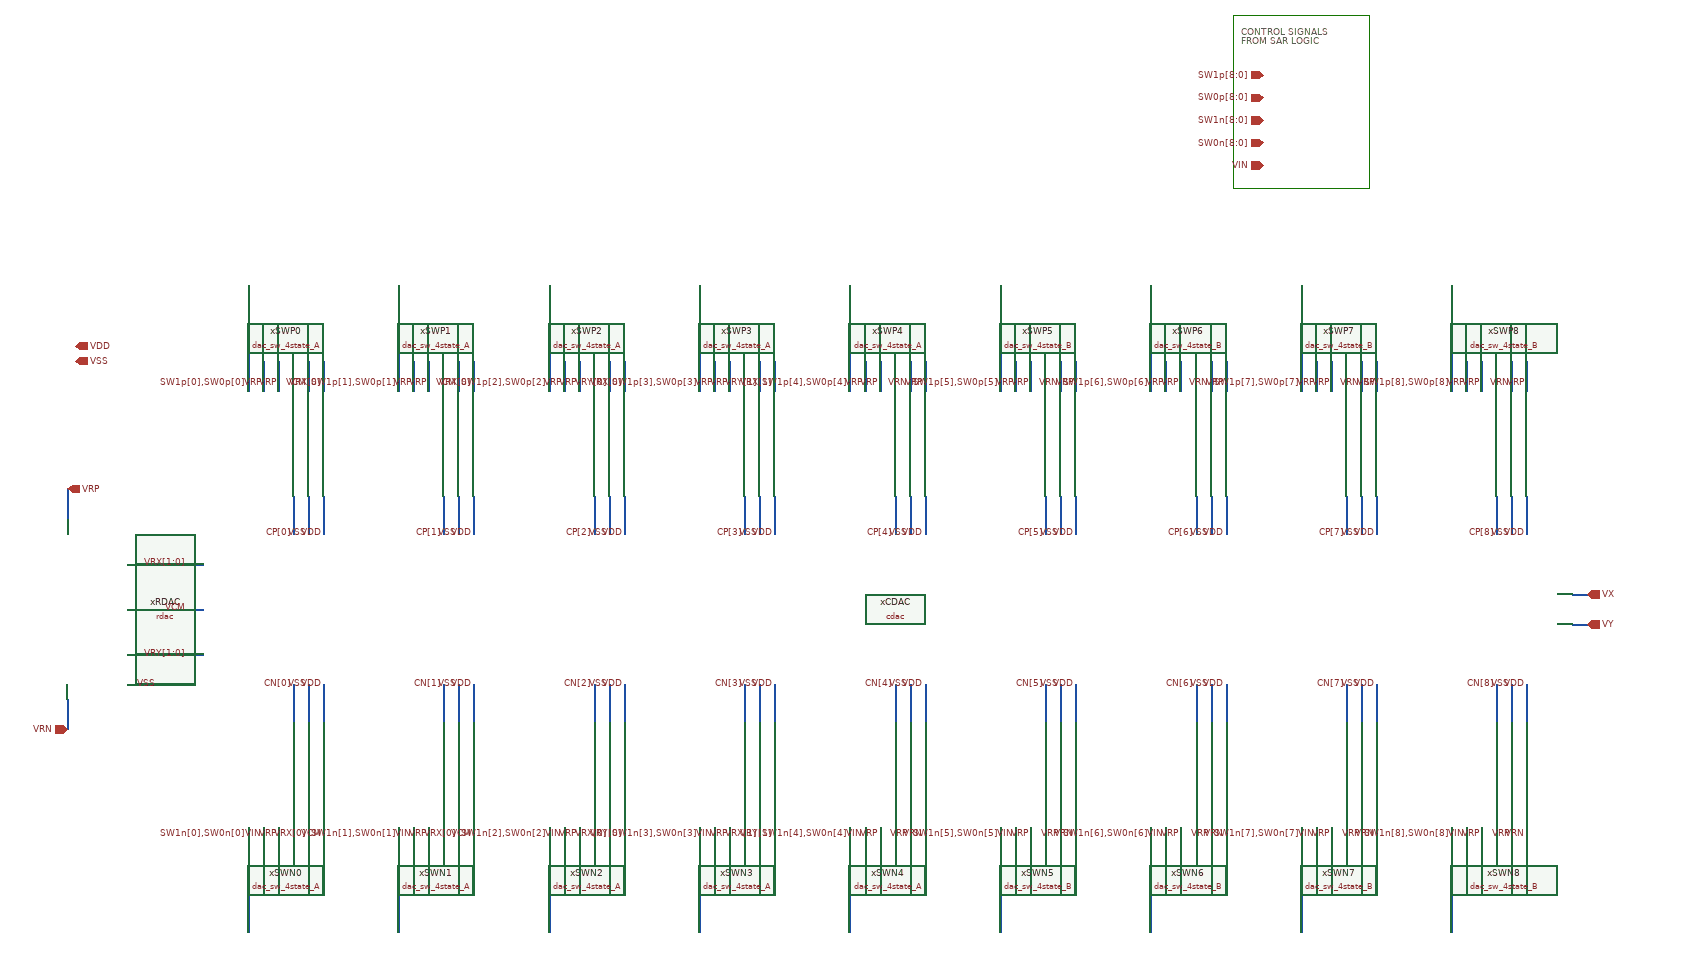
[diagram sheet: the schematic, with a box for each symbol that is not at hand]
v {xschem version=3.4.8RC file_version=1.3}
G {}
K {}
V {}
S {}
F {}
E {}
P 4 5 2070 -2150 2250 -2150 2250 -1920 2070 -1920 2070 -2150 {}
T {CONTROL SIGNALS
FROM SAR LOGIC} 2080 -2140 0 0 0.3 0.3 {}
N 520 -1520 520 -1480 {lab=VRP}
N 520 -1240 520 -1200 {lab=VRN}
N 600 -1260 640 -1260 {lab=VSS}
N 600 -1420 700 -1420 {lab=VRX[1:0]}
N 600 -1300 700 -1300 {lab=VRY[1:0]}
N 1660 -1690 1660 -1650 {lab=VRP}
N 1640 -1690 1640 -1650 {lab=VRN}
N 1600 -1690 1600 -1650 {lab=VRP}
N 1580 -1690 1580 -1650 {lab=VRP}
N 1660 -1510 1660 -1460 {lab=VDD}
N 1640 -1510 1640 -1460 {lab=VSS}
N 1620 -1510 1620 -1460 {lab=CP[4]}
N 1860 -1690 1860 -1650 {lab=VRP}
N 1840 -1690 1840 -1650 {lab=VRN}
N 1800 -1690 1800 -1650 {lab=VRP}
N 1780 -1690 1780 -1650 {lab=VRP}
N 1860 -1510 1860 -1460 {lab=VDD}
N 1840 -1510 1840 -1460 {lab=VSS}
N 1820 -1510 1820 -1460 {lab=CP[5]}
N 2060 -1690 2060 -1650 {lab=VRP}
N 2040 -1690 2040 -1650 {lab=VRN}
N 2000 -1690 2000 -1650 {lab=VRP}
N 1980 -1690 1980 -1650 {lab=VRP}
N 2060 -1510 2060 -1460 {lab=VDD}
N 2040 -1510 2040 -1460 {lab=VSS}
N 2020 -1510 2020 -1460 {lab=CP[6]}
N 2260 -1690 2260 -1650 {lab=VRP}
N 2240 -1690 2240 -1650 {lab=VRN}
N 2200 -1690 2200 -1650 {lab=VRP}
N 2180 -1690 2180 -1650 {lab=VRP}
N 2260 -1510 2260 -1460 {lab=VDD}
N 2240 -1510 2240 -1460 {lab=VSS}
N 2220 -1510 2220 -1460 {lab=CP[7]}
N 2440 -1690 2440 -1650 {lab=VRN}
N 2460 -1690 2460 -1650 {lab=VRP}
N 2400 -1690 2400 -1650 {lab=VRP}
N 2380 -1690 2380 -1650 {lab=VRP}
N 2460 -1510 2460 -1460 {lab=VDD}
N 2440 -1510 2440 -1460 {lab=VSS}
N 2420 -1510 2420 -1460 {lab=CP[8]}
N 1660 -1070 1660 -1030 {lab=VRN}
N 1640 -1070 1640 -1030 {lab=VRP}
N 1600 -1070 1600 -1030 {lab=VRP}
N 1580 -1070 1580 -1030 {lab=VIN}
N 1660 -1260 1660 -1210 {lab=VDD}
N 1640 -1260 1640 -1210 {lab=VSS}
N 1620 -1260 1620 -1210 {lab=CN[4]}
N 1860 -1070 1860 -1030 {lab=VRN}
N 1840 -1070 1840 -1030 {lab=VRP}
N 1800 -1070 1800 -1030 {lab=VRP}
N 1780 -1070 1780 -1030 {lab=VIN}
N 1860 -1260 1860 -1210 {lab=VDD}
N 1840 -1260 1840 -1210 {lab=VSS}
N 1820 -1260 1820 -1210 {lab=CN[5]}
N 2060 -1070 2060 -1030 {lab=VRN}
N 2040 -1070 2040 -1030 {lab=VRP}
N 2000 -1070 2000 -1030 {lab=VRP}
N 1980 -1070 1980 -1030 {lab=VIN}
N 2060 -1260 2060 -1210 {lab=VDD}
N 2040 -1260 2040 -1210 {lab=VSS}
N 2020 -1260 2020 -1210 {lab=CN[6]}
N 2260 -1070 2260 -1030 {lab=VRN}
N 2240 -1070 2240 -1030 {lab=VRP}
N 2200 -1070 2200 -1030 {lab=VRP}
N 2180 -1070 2180 -1030 {lab=VIN}
N 2260 -1260 2260 -1210 {lab=VDD}
N 2240 -1260 2240 -1210 {lab=VSS}
N 2220 -1260 2220 -1210 {lab=CN[7]}
N 2440 -1070 2440 -1030 {lab=VRP}
N 2460 -1070 2460 -1030 {lab=VRN}
N 2400 -1070 2400 -1030 {lab=VRP}
N 2380 -1070 2380 -1030 {lab=VIN}
N 2460 -1260 2460 -1210 {lab=VDD}
N 2440 -1260 2440 -1210 {lab=VSS}
N 2420 -1260 2420 -1210 {lab=CN[8]}
N 1560 -1790 1560 -1650 {lab=SW1p[4],SW0p[4]}
N 1560 -1070 1560 -930 {lab=SW1n[4],SW0n[4]}
N 1760 -1790 1760 -1650 {lab=SW1p[5],SW0p[5]}
N 1760 -1070 1760 -930 {lab=SW1n[5],SW0n[5]}
N 1960 -1790 1960 -1650 {lab=SW1p[6],SW0p[6]}
N 1960 -1070 1960 -930 {lab=SW1n[6],SW0n[6]}
N 2160 -1790 2160 -1650 {lab=SW1p[7],SW0p[7]}
N 2160 -1070 2160 -930 {lab=SW1n[7],SW0n[7]}
N 2360 -1790 2360 -1650 {lab=SW1p[8],SW0p[8]}
N 2360 -1070 2360 -930 {lab=SW1n[8],SW0n[8]}
N 800 -1690 800 -1650 {lab=VRP}
N 780 -1690 780 -1650 {lab=VRP}
N 860 -1510 860 -1460 {lab=VDD}
N 840 -1510 840 -1460 {lab=VSS}
N 820 -1510 820 -1460 {lab=CP[0]}
N 1000 -1690 1000 -1650 {lab=VRP}
N 980 -1690 980 -1650 {lab=VRP}
N 1060 -1510 1060 -1460 {lab=VDD}
N 1040 -1510 1040 -1460 {lab=VSS}
N 1020 -1510 1020 -1460 {lab=CP[1]}
N 1200 -1690 1200 -1650 {lab=VRP}
N 1180 -1690 1180 -1650 {lab=VRP}
N 1260 -1510 1260 -1460 {lab=VDD}
N 1240 -1510 1240 -1460 {lab=VSS}
N 1220 -1510 1220 -1460 {lab=CP[2]}
N 1400 -1690 1400 -1650 {lab=VRP}
N 1380 -1690 1380 -1650 {lab=VRP}
N 1460 -1510 1460 -1460 {lab=VDD}
N 1440 -1510 1440 -1460 {lab=VSS}
N 1420 -1510 1420 -1460 {lab=CP[3]}
N 800 -1070 800 -1030 {lab=VRP}
N 780 -1070 780 -1030 {lab=VIN}
N 860 -1260 860 -1210 {lab=VDD}
N 840 -1260 840 -1210 {lab=VSS}
N 820 -1260 820 -1210 {lab=CN[0]}
N 1000 -1070 1000 -1030 {lab=VRP}
N 980 -1070 980 -1030 {lab=VIN}
N 1060 -1260 1060 -1210 {lab=VDD}
N 1040 -1260 1040 -1210 {lab=VSS}
N 1020 -1260 1020 -1210 {lab=CN[1]}
N 1200 -1070 1200 -1030 {lab=VRP}
N 1180 -1070 1180 -1030 {lab=VIN}
N 1260 -1260 1260 -1210 {lab=VDD}
N 1240 -1260 1240 -1210 {lab=VSS}
N 1220 -1260 1220 -1210 {lab=CN[2]}
N 1400 -1070 1400 -1030 {lab=VRP}
N 1380 -1070 1380 -1030 {lab=VIN}
N 1460 -1260 1460 -1210 {lab=VDD}
N 1440 -1260 1440 -1210 {lab=VSS}
N 1420 -1260 1420 -1210 {lab=CN[3]}
N 760 -1790 760 -1650 {lab=SW1p[0],SW0p[0]}
N 760 -1070 760 -930 {lab=SW1n[0],SW0n[0]}
N 960 -1790 960 -1650 {lab=SW1p[1],SW0p[1]}
N 960 -1070 960 -930 {lab=SW1n[1],SW0n[1]}
N 1160 -1790 1160 -1650 {lab=SW1p[2],SW0p[2]}
N 1160 -1070 1160 -930 {lab=SW1n[2],SW0n[2]}
N 1360 -1790 1360 -1650 {lab=SW1p[3],SW0p[3]}
N 1360 -1070 1360 -930 {lab=SW1n[3],SW0n[3]}
N 1260 -1690 1260 -1650 {lab=VRX[0]}
N 1240 -1690 1240 -1650 {lab=VRY[0]}
N 1460 -1690 1460 -1650 {lab=VRX[1]}
N 1440 -1690 1440 -1650 {lab=VRY[1]}
N 860 -1690 860 -1650 {lab=VRX[0]}
N 840 -1690 840 -1650 {lab=VCM}
N 1060 -1690 1060 -1650 {lab=VRX[0]}
N 1040 -1690 1040 -1650 {lab=VCM}
N 1260 -1070 1260 -1030 {lab=VRY[0]}
N 1240 -1070 1240 -1030 {lab=VRX[0]}
N 1460 -1070 1460 -1030 {lab=VRY[1]}
N 1440 -1070 1440 -1030 {lab=VRX[1]}
N 860 -1070 860 -1030 {lab=VCM}
N 840 -1070 840 -1030 {lab=VRX[0]}
N 1060 -1070 1060 -1030 {lab=VCM}
N 1040 -1070 1040 -1030 {lab=VRX[0]}
N 600 -1360 700 -1360 {lab=VCM}
N 2520 -1380 2540 -1380 {lab=VX}
N 2520 -1340 2540 -1340 {lab=VY}
C {designs/sar_adc/dac/rdac/xschem/rdac.sym} 520 -1360 0 0 {name=xRDAC}
C {lab_wire.sym} 640 -1260 0 0 {name=p2 sig_type=std_logic lab=VSS}
C {lab_wire.sym} 680 -1360 0 0 {name=p3 sig_type=std_logic lab=VCM}
C {lab_wire.sym} 680 -1420 0 0 {name=p4 sig_type=std_logic lab=VRX[1:0]}
C {lab_wire.sym} 680 -1300 0 0 {name=p5 sig_type=std_logic lab=VRY[1:0]}
C {iopin.sym} 530 -1690 0 1 {name=p156 lab=VSS}
C {iopin.sym} 530 -1710 0 1 {name=p157 lab=VDD}
C {ipin.sym} 520 -1520 3 1 {name=p158 lab=VRP}
C {ipin.sym} 520 -1200 3 0 {name=p159 lab=VRN}
C {designs/sar_adc/dac/cdac/xschem/cdac.sym} 1620 -1360 0 0 {name=xCDAC}
C {designs/sar_adc/dac/dac_sw_4state_A/xschem/dac_sw_4state_A.sym} 1620 -1580 1 0 {name=xSWP4}
C {lab_wire.sym} 1660 -1660 1 0 {name=p37 sig_type=std_logic lab=VRP}
C {lab_wire.sym} 1640 -1660 1 0 {name=p38 sig_type=std_logic lab=VRN}
C {lab_wire.sym} 1600 -1660 1 0 {name=p39 sig_type=std_logic lab=VRP}
C {lab_wire.sym} 1580 -1660 1 0 {name=p40 sig_type=std_logic lab=VRP}
C {lab_wire.sym} 1660 -1460 1 0 {name=p41 sig_type=std_logic lab=VDD}
C {lab_wire.sym} 1640 -1460 1 0 {name=p42 sig_type=std_logic lab=VSS}
C {lab_wire.sym} 1620 -1460 1 0 {name=p43 sig_type=std_logic lab=CP[4]}
C {designs/sar_adc/dac/dac_sw_4state_B/xschem/dac_sw_4state_B.sym} 1820 -1580 1 0 {name=xSWP5}
C {lab_wire.sym} 1860 -1660 1 0 {name=p44 sig_type=std_logic lab=VRP}
C {lab_wire.sym} 1840 -1660 1 0 {name=p45 sig_type=std_logic lab=VRN}
C {lab_wire.sym} 1800 -1660 1 0 {name=p46 sig_type=std_logic lab=VRP}
C {lab_wire.sym} 1780 -1660 1 0 {name=p47 sig_type=std_logic lab=VRP}
C {lab_wire.sym} 1860 -1460 1 0 {name=p48 sig_type=std_logic lab=VDD}
C {lab_wire.sym} 1840 -1460 1 0 {name=p49 sig_type=std_logic lab=VSS}
C {lab_wire.sym} 1820 -1460 1 0 {name=p50 sig_type=std_logic lab=CP[5]}
C {designs/sar_adc/dac/dac_sw_4state_B/xschem/dac_sw_4state_B.sym} 2020 -1580 1 0 {name=xSWP6}
C {lab_wire.sym} 2060 -1660 1 0 {name=p51 sig_type=std_logic lab=VRP}
C {lab_wire.sym} 2040 -1660 1 0 {name=p52 sig_type=std_logic lab=VRN}
C {lab_wire.sym} 2000 -1660 1 0 {name=p53 sig_type=std_logic lab=VRP}
C {lab_wire.sym} 1980 -1660 1 0 {name=p54 sig_type=std_logic lab=VRP}
C {lab_wire.sym} 2060 -1460 1 0 {name=p55 sig_type=std_logic lab=VDD}
C {lab_wire.sym} 2040 -1460 1 0 {name=p56 sig_type=std_logic lab=VSS}
C {lab_wire.sym} 2020 -1460 1 0 {name=p57 sig_type=std_logic lab=CP[6]}
C {designs/sar_adc/dac/dac_sw_4state_B/xschem/dac_sw_4state_B.sym} 2220 -1580 1 0 {name=xSWP7}
C {lab_wire.sym} 2260 -1660 1 0 {name=p58 sig_type=std_logic lab=VRP}
C {lab_wire.sym} 2240 -1660 1 0 {name=p59 sig_type=std_logic lab=VRN}
C {lab_wire.sym} 2200 -1660 1 0 {name=p60 sig_type=std_logic lab=VRP}
C {lab_wire.sym} 2180 -1660 1 0 {name=p61 sig_type=std_logic lab=VRP}
C {lab_wire.sym} 2260 -1460 1 0 {name=p62 sig_type=std_logic lab=VDD}
C {lab_wire.sym} 2240 -1460 1 0 {name=p63 sig_type=std_logic lab=VSS}
C {lab_wire.sym} 2220 -1460 1 0 {name=p64 sig_type=std_logic lab=CP[7]}
C {designs/sar_adc/dac/dac_sw_4state_B/xschem/dac_sw_4state_B.sym} 2420 -1580 1 0 {name=xSWP8}
C {lab_wire.sym} 2460 -1660 1 0 {name=p65 sig_type=std_logic lab=VRP}
C {lab_wire.sym} 2440 -1660 1 0 {name=p66 sig_type=std_logic lab=VRN}
C {lab_wire.sym} 2400 -1660 1 0 {name=p67 sig_type=std_logic lab=VRP}
C {lab_wire.sym} 2380 -1660 1 0 {name=p68 sig_type=std_logic lab=VRP}
C {lab_wire.sym} 2460 -1460 1 0 {name=p69 sig_type=std_logic lab=VDD}
C {lab_wire.sym} 2440 -1460 1 0 {name=p70 sig_type=std_logic lab=VSS}
C {designs/sar_adc/dac/dac_sw_4state_A/xschem/dac_sw_4state_A.sym} 1620 -1140 1 1 {name=xSWN4}
C {lab_wire.sym} 1640 -1060 1 1 {name=p100 sig_type=std_logic lab=VRP}
C {lab_wire.sym} 1660 -1060 1 1 {name=p101 sig_type=std_logic lab=VRN}
C {lab_wire.sym} 1600 -1060 1 1 {name=p102 sig_type=std_logic lab=VRP}
C {lab_wire.sym} 1580 -1060 1 1 {name=p103 sig_type=std_logic lab=VIN}
C {lab_wire.sym} 1660 -1260 1 1 {name=p104 sig_type=std_logic lab=VDD}
C {lab_wire.sym} 1640 -1260 1 1 {name=p105 sig_type=std_logic lab=VSS}
C {lab_wire.sym} 1620 -1260 1 1 {name=p106 sig_type=std_logic lab=CN[4]}
C {designs/sar_adc/dac/dac_sw_4state_B/xschem/dac_sw_4state_B.sym} 1820 -1140 1 1 {name=xSWN5}
C {lab_wire.sym} 1840 -1060 1 1 {name=p107 sig_type=std_logic lab=VRP}
C {lab_wire.sym} 1860 -1060 1 1 {name=p108 sig_type=std_logic lab=VRN}
C {lab_wire.sym} 1800 -1060 1 1 {name=p109 sig_type=std_logic lab=VRP}
C {lab_wire.sym} 1780 -1060 1 1 {name=p110 sig_type=std_logic lab=VIN}
C {lab_wire.sym} 1860 -1260 1 1 {name=p111 sig_type=std_logic lab=VDD}
C {lab_wire.sym} 1840 -1260 1 1 {name=p112 sig_type=std_logic lab=VSS}
C {lab_wire.sym} 1820 -1260 1 1 {name=p113 sig_type=std_logic lab=CN[5]}
C {designs/sar_adc/dac/dac_sw_4state_B/xschem/dac_sw_4state_B.sym} 2020 -1140 1 1 {name=xSWN6}
C {lab_wire.sym} 2040 -1060 1 1 {name=p114 sig_type=std_logic lab=VRP}
C {lab_wire.sym} 2060 -1060 1 1 {name=p115 sig_type=std_logic lab=VRN}
C {lab_wire.sym} 2000 -1060 1 1 {name=p116 sig_type=std_logic lab=VRP}
C {lab_wire.sym} 1980 -1060 1 1 {name=p117 sig_type=std_logic lab=VIN}
C {lab_wire.sym} 2060 -1260 1 1 {name=p118 sig_type=std_logic lab=VDD}
C {lab_wire.sym} 2040 -1260 1 1 {name=p119 sig_type=std_logic lab=VSS}
C {lab_wire.sym} 2020 -1260 1 1 {name=p120 sig_type=std_logic lab=CN[6]}
C {designs/sar_adc/dac/dac_sw_4state_B/xschem/dac_sw_4state_B.sym} 2220 -1140 1 1 {name=xSWN7}
C {lab_wire.sym} 2240 -1060 1 1 {name=p121 sig_type=std_logic lab=VRP}
C {lab_wire.sym} 2260 -1060 1 1 {name=p122 sig_type=std_logic lab=VRN}
C {lab_wire.sym} 2200 -1060 1 1 {name=p123 sig_type=std_logic lab=VRP}
C {lab_wire.sym} 2180 -1060 1 1 {name=p124 sig_type=std_logic lab=VIN}
C {lab_wire.sym} 2260 -1260 1 1 {name=p125 sig_type=std_logic lab=VDD}
C {lab_wire.sym} 2240 -1260 1 1 {name=p126 sig_type=std_logic lab=VSS}
C {lab_wire.sym} 2220 -1260 1 1 {name=p127 sig_type=std_logic lab=CN[7]}
C {designs/sar_adc/dac/dac_sw_4state_B/xschem/dac_sw_4state_B.sym} 2420 -1140 1 1 {name=xSWN8}
C {lab_wire.sym} 2440 -1060 1 1 {name=p128 sig_type=std_logic lab=VRP}
C {lab_wire.sym} 2460 -1060 1 1 {name=p129 sig_type=std_logic lab=VRN}
C {lab_wire.sym} 2400 -1060 1 1 {name=p130 sig_type=std_logic lab=VRP}
C {lab_wire.sym} 2380 -1060 1 1 {name=p131 sig_type=std_logic lab=VIN}
C {lab_wire.sym} 2460 -1260 1 1 {name=p132 sig_type=std_logic lab=VDD}
C {lab_wire.sym} 2440 -1260 1 1 {name=p133 sig_type=std_logic lab=VSS}
C {lab_wire.sym} 1560 -1660 1 0 {name=p164 sig_type=std_logic lab=SW1p[4],SW0p[4]}
C {lab_wire.sym} 1560 -1060 1 1 {name=p165 sig_type=std_logic lab=SW1n[4],SW0n[4]}
C {lab_wire.sym} 1760 -1660 1 0 {name=p166 sig_type=std_logic lab=SW1p[5],SW0p[5]}
C {lab_wire.sym} 1760 -1060 1 1 {name=p167 sig_type=std_logic lab=SW1n[5],SW0n[5]}
C {lab_wire.sym} 1960 -1660 1 0 {name=p168 sig_type=std_logic lab=SW1p[6],SW0p[6]}
C {lab_wire.sym} 1960 -1060 1 1 {name=p169 sig_type=std_logic lab=SW1n[6],SW0n[6]}
C {lab_wire.sym} 2160 -1660 1 0 {name=p170 sig_type=std_logic lab=SW1p[7],SW0p[7]}
C {lab_wire.sym} 2160 -1060 1 1 {name=p171 sig_type=std_logic lab=SW1n[7],SW0n[7]}
C {lab_wire.sym} 2360 -1660 1 0 {name=p172 sig_type=std_logic lab=SW1p[8],SW0p[8]}
C {lab_wire.sym} 2420 -1460 1 0 {name=p173 sig_type=std_logic lab=CP[8]}
C {lab_wire.sym} 2420 -1260 1 1 {name=p71 sig_type=std_logic lab=CN[8]}
C {lab_wire.sym} 2360 -1060 1 1 {name=p134 sig_type=std_logic lab=SW1n[8],SW0n[8]}
C {designs/sar_adc/dac/dac_sw_4state_A/xschem/dac_sw_4state_A.sym} 820 -1580 1 0 {name=xSWP0}
C {lab_wire.sym} 800 -1660 1 0 {name=p12 sig_type=std_logic lab=VRP}
C {lab_wire.sym} 780 -1660 1 0 {name=p13 sig_type=std_logic lab=VRP}
C {lab_wire.sym} 860 -1460 1 0 {name=p14 sig_type=std_logic lab=VDD}
C {lab_wire.sym} 840 -1460 1 0 {name=p15 sig_type=std_logic lab=VSS}
C {lab_wire.sym} 820 -1460 1 0 {name=p16 sig_type=std_logic lab=CP[0]}
C {designs/sar_adc/dac/dac_sw_4state_A/xschem/dac_sw_4state_A.sym} 1020 -1580 1 0 {name=xSWP1}
C {lab_wire.sym} 1000 -1660 1 0 {name=p17 sig_type=std_logic lab=VRP}
C {lab_wire.sym} 980 -1660 1 0 {name=p18 sig_type=std_logic lab=VRP}
C {lab_wire.sym} 1060 -1460 1 0 {name=p19 sig_type=std_logic lab=VDD}
C {lab_wire.sym} 1040 -1460 1 0 {name=p20 sig_type=std_logic lab=VSS}
C {lab_wire.sym} 1020 -1460 1 0 {name=p21 sig_type=std_logic lab=CP[1]}
C {designs/sar_adc/dac/dac_sw_4state_A/xschem/dac_sw_4state_A.sym} 1220 -1580 1 0 {name=xSWP2}
C {lab_wire.sym} 1200 -1660 1 0 {name=p25 sig_type=std_logic lab=VRP}
C {lab_wire.sym} 1180 -1660 1 0 {name=p26 sig_type=std_logic lab=VRP}
C {lab_wire.sym} 1260 -1460 1 0 {name=p27 sig_type=std_logic lab=VDD}
C {lab_wire.sym} 1240 -1460 1 0 {name=p28 sig_type=std_logic lab=VSS}
C {lab_wire.sym} 1220 -1460 1 0 {name=p29 sig_type=std_logic lab=CP[2]}
C {designs/sar_adc/dac/dac_sw_4state_A/xschem/dac_sw_4state_A.sym} 1420 -1580 1 0 {name=xSWP3}
C {lab_wire.sym} 1400 -1660 1 0 {name=p32 sig_type=std_logic lab=VRP}
C {lab_wire.sym} 1380 -1660 1 0 {name=p33 sig_type=std_logic lab=VRP}
C {lab_wire.sym} 1460 -1460 1 0 {name=p34 sig_type=std_logic lab=VDD}
C {lab_wire.sym} 1440 -1460 1 0 {name=p35 sig_type=std_logic lab=VSS}
C {lab_wire.sym} 1420 -1460 1 0 {name=p36 sig_type=std_logic lab=CP[3]}
C {designs/sar_adc/dac/dac_sw_4state_A/xschem/dac_sw_4state_A.sym} 820 -1140 1 1 {name=xSWN0}
C {lab_wire.sym} 800 -1060 1 1 {name=p74 sig_type=std_logic lab=VRP}
C {lab_wire.sym} 780 -1060 1 1 {name=p75 sig_type=std_logic lab=VIN}
C {lab_wire.sym} 860 -1260 1 1 {name=p76 sig_type=std_logic lab=VDD}
C {lab_wire.sym} 840 -1260 1 1 {name=p77 sig_type=std_logic lab=VSS}
C {lab_wire.sym} 820 -1260 1 1 {name=p78 sig_type=std_logic lab=CN[0]}
C {designs/sar_adc/dac/dac_sw_4state_A/xschem/dac_sw_4state_A.sym} 1020 -1140 1 1 {name=xSWN1}
C {lab_wire.sym} 1000 -1060 1 1 {name=p81 sig_type=std_logic lab=VRP}
C {lab_wire.sym} 980 -1060 1 1 {name=p82 sig_type=std_logic lab=VIN}
C {lab_wire.sym} 1060 -1260 1 1 {name=p83 sig_type=std_logic lab=VDD}
C {lab_wire.sym} 1040 -1260 1 1 {name=p84 sig_type=std_logic lab=VSS}
C {lab_wire.sym} 1020 -1260 1 1 {name=p85 sig_type=std_logic lab=CN[1]}
C {designs/sar_adc/dac/dac_sw_4state_A/xschem/dac_sw_4state_A.sym} 1220 -1140 1 1 {name=xSWN2}
C {lab_wire.sym} 1200 -1060 1 1 {name=p88 sig_type=std_logic lab=VRP}
C {lab_wire.sym} 1180 -1060 1 1 {name=p89 sig_type=std_logic lab=VIN}
C {lab_wire.sym} 1260 -1260 1 1 {name=p90 sig_type=std_logic lab=VDD}
C {lab_wire.sym} 1240 -1260 1 1 {name=p91 sig_type=std_logic lab=VSS}
C {lab_wire.sym} 1220 -1260 1 1 {name=p92 sig_type=std_logic lab=CN[2]}
C {designs/sar_adc/dac/dac_sw_4state_A/xschem/dac_sw_4state_A.sym} 1420 -1140 1 1 {name=xSWN3}
C {lab_wire.sym} 1400 -1060 1 1 {name=p95 sig_type=std_logic lab=VRP}
C {lab_wire.sym} 1380 -1060 1 1 {name=p96 sig_type=std_logic lab=VIN}
C {lab_wire.sym} 1460 -1260 1 1 {name=p97 sig_type=std_logic lab=VDD}
C {lab_wire.sym} 1440 -1260 1 1 {name=p98 sig_type=std_logic lab=VSS}
C {lab_wire.sym} 1420 -1260 1 1 {name=p99 sig_type=std_logic lab=CN[3]}
C {lab_wire.sym} 760 -1660 1 0 {name=p154 sig_type=std_logic lab=SW1p[0],SW0p[0]}
C {lab_wire.sym} 760 -1060 1 1 {name=p155 sig_type=std_logic lab=SW1n[0],SW0n[0]}
C {lab_wire.sym} 960 -1660 1 0 {name=p142 sig_type=std_logic lab=SW1p[1],SW0p[1]}
C {lab_wire.sym} 960 -1060 1 1 {name=p153 sig_type=std_logic lab=SW1n[1],SW0n[1]}
C {lab_wire.sym} 1160 -1660 1 0 {name=p7 sig_type=std_logic lab=SW1p[2],SW0p[2]}
C {lab_wire.sym} 1160 -1060 1 1 {name=p9 sig_type=std_logic lab=SW1n[2],SW0n[2]}
C {lab_wire.sym} 1360 -1660 1 0 {name=p162 sig_type=std_logic lab=SW1p[3],SW0p[3]}
C {lab_wire.sym} 1360 -1060 1 1 {name=p163 sig_type=std_logic lab=SW1n[3],SW0n[3]}
C {lab_wire.sym} 1260 -1660 1 0 {name=p10 sig_type=std_logic lab=VRX[0]}
C {lab_wire.sym} 1240 -1660 1 0 {name=p11 sig_type=std_logic lab=VRY[0]}
C {lab_wire.sym} 1460 -1660 1 0 {name=p6 sig_type=std_logic lab=VRX[1]}
C {lab_wire.sym} 1440 -1660 1 0 {name=p8 sig_type=std_logic lab=VRY[1]}
C {lab_wire.sym} 860 -1660 1 0 {name=p23 sig_type=std_logic lab=VRX[0]}
C {lab_wire.sym} 840 -1660 1 0 {name=p24 sig_type=std_logic lab=VCM}
C {lab_wire.sym} 1060 -1660 1 0 {name=p30 sig_type=std_logic lab=VRX[0]}
C {lab_wire.sym} 1040 -1660 1 0 {name=p31 sig_type=std_logic lab=VCM}
C {lab_wire.sym} 1240 -1060 1 1 {name=p72 sig_type=std_logic lab=VRX[0]}
C {lab_wire.sym} 1260 -1060 1 1 {name=p73 sig_type=std_logic lab=VRY[0]}
C {lab_wire.sym} 1440 -1060 1 1 {name=p79 sig_type=std_logic lab=VRX[1]}
C {lab_wire.sym} 1460 -1060 1 1 {name=p80 sig_type=std_logic lab=VRY[1]}
C {lab_wire.sym} 840 -1060 1 1 {name=p86 sig_type=std_logic lab=VRX[0]}
C {lab_wire.sym} 860 -1060 1 1 {name=p87 sig_type=std_logic lab=VCM}
C {lab_wire.sym} 1040 -1060 1 1 {name=p93 sig_type=std_logic lab=VRX[0]}
C {lab_wire.sym} 1060 -1060 1 1 {name=p94 sig_type=std_logic lab=VCM}
C {noconn.sym} 700 -1360 0 1 {name=l1}
C {iopin.sym} 2110 -2070 0 0 {name=p138 lab=SW1p[8:0]}
C {iopin.sym} 2110 -2040 0 0 {name=p141 lab=SW0p[8:0]}
C {iopin.sym} 2110 -2010 0 0 {name=p147 lab=SW1n[8:0]}
C {iopin.sym} 2110 -1980 0 0 {name=p149 lab=SW0n[8:0]}
C {iopin.sym} 2110 -1950 0 0 {name=p1 lab=VIN}
C {opin.sym} 2540 -1380 0 0 {name=p22 lab=VX}
C {opin.sym} 2540 -1340 0 0 {name=p135 lab=VY
}
